VERSION 5.7 ;
  NOWIREEXTENSIONATPIN ON ;
  DIVIDERCHAR "/" ;
  BUSBITCHARS "[]" ;
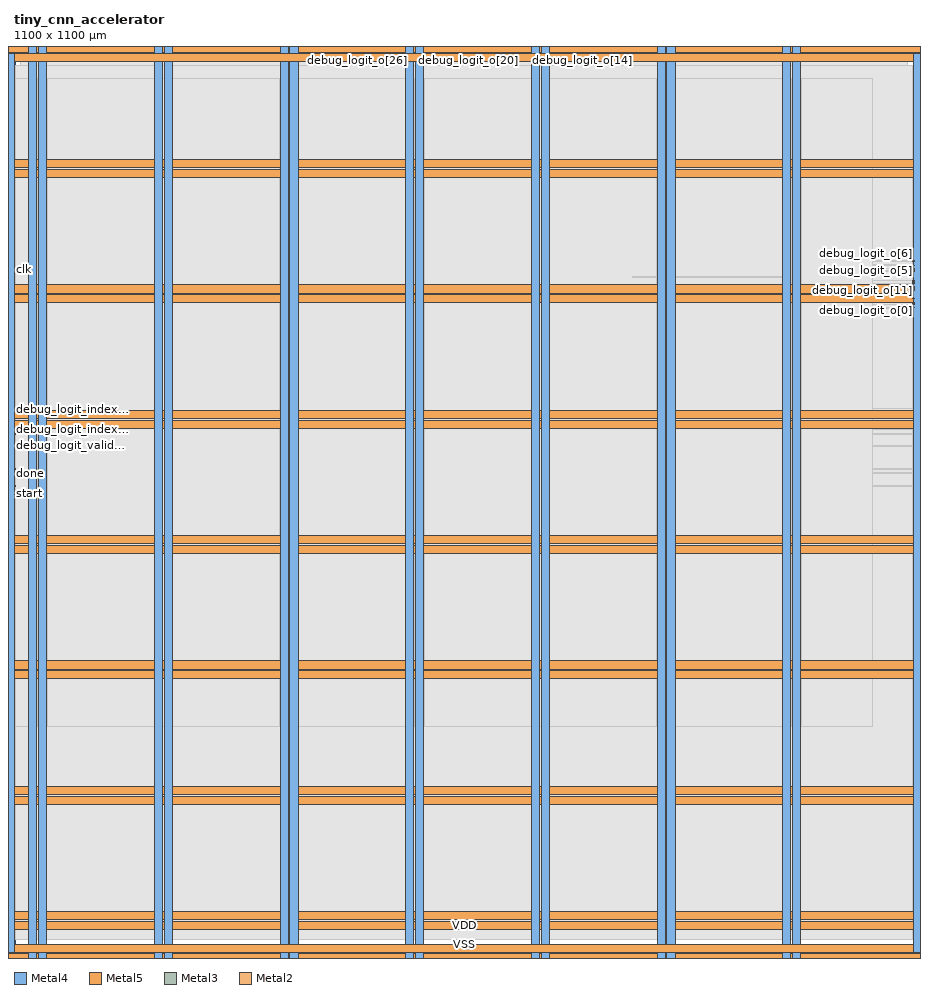
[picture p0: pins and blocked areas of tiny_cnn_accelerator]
MACRO tiny_cnn_accelerator
  CLASS BLOCK ;
  FOREIGN tiny_cnn_accelerator ;
  ORIGIN 0.000 0.000 ;
  SIZE 1100.000 BY 1100.000 ;
  PIN VDD
    DIRECTION INOUT ;
    USE POWER ;
    PORT
      LAYER Metal4 ;
        RECT -9.280 -0.320 0.720 1097.920 ;
    END
    PORT
      LAYER Metal4 ;
        RECT 1099.120 -0.320 1109.120 1097.920 ;
    END
    PORT
      LAYER Metal5 ;
        RECT -9.280 -0.320 1109.120 9.680 ;
    END
    PORT
      LAYER Metal5 ;
        RECT -9.280 1087.920 1109.120 1097.920 ;
    END
    PORT
      LAYER Metal4 ;
        RECT 18.040 -12.020 28.040 1109.620 ;
    END
    PORT
      LAYER Metal4 ;
        RECT 171.640 -12.020 181.640 1109.620 ;
    END
    PORT
      LAYER Metal4 ;
        RECT 325.240 -12.020 335.240 1109.620 ;
    END
    PORT
      LAYER Metal4 ;
        RECT 478.840 -12.020 488.840 1109.620 ;
    END
    PORT
      LAYER Metal4 ;
        RECT 632.440 -12.020 642.440 1109.620 ;
    END
    PORT
      LAYER Metal4 ;
        RECT 786.040 -12.020 796.040 1109.620 ;
    END
    PORT
      LAYER Metal4 ;
        RECT 939.640 -12.020 949.640 1109.620 ;
    END
    PORT
      LAYER Metal5 ;
        RECT -20.980 27.330 1120.820 37.330 ;
    END
    PORT
      LAYER Metal5 ;
        RECT -20.980 180.510 1120.820 190.510 ;
    END
    PORT
      LAYER Metal5 ;
        RECT -20.980 333.690 1120.820 343.690 ;
    END
    PORT
      LAYER Metal5 ;
        RECT -20.980 486.870 1120.820 496.870 ;
    END
    PORT
      LAYER Metal5 ;
        RECT -20.980 640.050 1120.820 650.050 ;
    END
    PORT
      LAYER Metal5 ;
        RECT -20.980 793.230 1120.820 803.230 ;
    END
    PORT
      LAYER Metal5 ;
        RECT -20.980 946.410 1120.820 956.410 ;
    END
  END VDD
  PIN VSS
    DIRECTION INOUT ;
    USE GROUND ;
    PORT
      LAYER Metal4 ;
        RECT -20.980 -12.020 -10.980 1109.620 ;
    END
    PORT
      LAYER Metal4 ;
        RECT 1110.820 -12.020 1120.820 1109.620 ;
    END
    PORT
      LAYER Metal5 ;
        RECT -20.980 -12.020 1120.820 -2.020 ;
    END
    PORT
      LAYER Metal5 ;
        RECT -20.980 1099.620 1120.820 1109.620 ;
    END
    PORT
      LAYER Metal4 ;
        RECT 30.040 -12.020 40.040 1109.620 ;
    END
    PORT
      LAYER Metal4 ;
        RECT 183.640 -12.020 193.640 1109.620 ;
    END
    PORT
      LAYER Metal4 ;
        RECT 337.240 -12.020 347.240 1109.620 ;
    END
    PORT
      LAYER Metal4 ;
        RECT 490.840 -12.020 500.840 1109.620 ;
    END
    PORT
      LAYER Metal4 ;
        RECT 644.440 -12.020 654.440 1109.620 ;
    END
    PORT
      LAYER Metal4 ;
        RECT 798.040 -12.020 808.040 1109.620 ;
    END
    PORT
      LAYER Metal4 ;
        RECT 951.640 -12.020 961.640 1109.620 ;
    END
    PORT
      LAYER Metal5 ;
        RECT -20.980 39.330 1120.820 49.330 ;
    END
    PORT
      LAYER Metal5 ;
        RECT -20.980 192.510 1120.820 202.510 ;
    END
    PORT
      LAYER Metal5 ;
        RECT -20.980 345.690 1120.820 355.690 ;
    END
    PORT
      LAYER Metal5 ;
        RECT -20.980 498.870 1120.820 508.870 ;
    END
    PORT
      LAYER Metal5 ;
        RECT -20.980 652.050 1120.820 662.050 ;
    END
    PORT
      LAYER Metal5 ;
        RECT -20.980 805.230 1120.820 815.230 ;
    END
    PORT
      LAYER Metal5 ;
        RECT -20.980 958.410 1120.820 968.410 ;
    END
  END VSS
  PIN busy
    DIRECTION OUTPUT ;
    USE SIGNAL ;
    ANTENNADIFFAREA 1.986000 ;
    PORT
      LAYER Metal3 ;
        RECT 0.000 590.170 2.000 590.870 ;
    END
  END busy
  PIN clk
    DIRECTION INPUT ;
    USE SIGNAL ;
    ANTENNAGATEAREA 4.738000 ;
    PORT
      LAYER Metal3 ;
        RECT 0.000 834.330 2.000 835.030 ;
    END
  END clk
  PIN debug_logit_index_o[0]
    DIRECTION OUTPUT ;
    USE SIGNAL ;
    ANTENNADIFFAREA 1.986000 ;
    PORT
      LAYER Metal3 ;
        RECT 0.000 638.330 2.000 639.030 ;
    END
  END debug_logit_index_o[0]
  PIN debug_logit_index_o[1]
    DIRECTION OUTPUT ;
    USE SIGNAL ;
    ANTENNADIFFAREA 1.986000 ;
    PORT
      LAYER Metal3 ;
        RECT 0.000 632.730 2.000 633.430 ;
    END
  END debug_logit_index_o[1]
  PIN debug_logit_index_o[2]
    DIRECTION OUTPUT ;
    USE SIGNAL ;
    ANTENNADIFFAREA 1.986000 ;
    PORT
      LAYER Metal3 ;
        RECT 0.000 662.970 2.000 663.670 ;
    END
  END debug_logit_index_o[2]
  PIN debug_logit_index_o[3]
    DIRECTION OUTPUT ;
    USE SIGNAL ;
    ANTENNADIFFAREA 1.986000 ;
    PORT
      LAYER Metal3 ;
        RECT 0.000 661.850 2.000 662.550 ;
    END
  END debug_logit_index_o[3]
  PIN debug_logit_o[0]
    DIRECTION OUTPUT ;
    USE SIGNAL ;
    ANTENNADIFFAREA 1.986000 ;
    PORT
      LAYER Metal3 ;
        RECT 1098.000 792.890 1100.000 793.590 ;
    END
  END debug_logit_o[0]
  PIN debug_logit_o[10]
    DIRECTION OUTPUT ;
    USE SIGNAL ;
    ANTENNADIFFAREA 1.986000 ;
    PORT
      LAYER Metal3 ;
        RECT 1098.000 811.930 1100.000 812.630 ;
    END
  END debug_logit_o[10]
  PIN debug_logit_o[11]
    DIRECTION OUTPUT ;
    USE SIGNAL ;
    ANTENNADIFFAREA 1.986000 ;
    PORT
      LAYER Metal3 ;
        RECT 1098.000 808.570 1100.000 809.270 ;
    END
  END debug_logit_o[11]
  PIN debug_logit_o[12]
    DIRECTION OUTPUT ;
    USE SIGNAL ;
    ANTENNADIFFAREA 1.986000 ;
    PORT
      LAYER Metal2 ;
        RECT 731.290 1098.000 731.990 1100.000 ;
    END
  END debug_logit_o[12]
  PIN debug_logit_o[13]
    DIRECTION OUTPUT ;
    USE SIGNAL ;
    ANTENNADIFFAREA 1.986000 ;
    PORT
      LAYER Metal2 ;
        RECT 713.370 1098.000 714.070 1100.000 ;
    END
  END debug_logit_o[13]
  PIN debug_logit_o[14]
    DIRECTION OUTPUT ;
    USE SIGNAL ;
    ANTENNADIFFAREA 1.986000 ;
    PORT
      LAYER Metal2 ;
        RECT 694.330 1098.000 695.030 1100.000 ;
    END
  END debug_logit_o[14]
  PIN debug_logit_o[15]
    DIRECTION OUTPUT ;
    USE SIGNAL ;
    ANTENNADIFFAREA 1.986000 ;
    PORT
      LAYER Metal2 ;
        RECT 657.370 1098.000 658.070 1100.000 ;
    END
  END debug_logit_o[15]
  PIN debug_logit_o[16]
    DIRECTION OUTPUT ;
    USE SIGNAL ;
    ANTENNADIFFAREA 1.986000 ;
    PORT
      LAYER Metal2 ;
        RECT 610.330 1098.000 611.030 1100.000 ;
    END
  END debug_logit_o[16]
  PIN debug_logit_o[17]
    DIRECTION OUTPUT ;
    USE SIGNAL ;
    ANTENNADIFFAREA 1.986000 ;
    PORT
      LAYER Metal2 ;
        RECT 606.970 1098.000 607.670 1100.000 ;
    END
  END debug_logit_o[17]
  PIN debug_logit_o[18]
    DIRECTION OUTPUT ;
    USE SIGNAL ;
    ANTENNADIFFAREA 1.986000 ;
    PORT
      LAYER Metal2 ;
        RECT 584.570 1098.000 585.270 1100.000 ;
    END
  END debug_logit_o[18]
  PIN debug_logit_o[19]
    DIRECTION OUTPUT ;
    USE SIGNAL ;
    ANTENNADIFFAREA 1.986000 ;
    PORT
      LAYER Metal2 ;
        RECT 566.650 1098.000 567.350 1100.000 ;
    END
  END debug_logit_o[19]
  PIN debug_logit_o[1]
    DIRECTION OUTPUT ;
    USE SIGNAL ;
    ANTENNADIFFAREA 1.986000 ;
    PORT
      LAYER Metal3 ;
        RECT 1098.000 817.530 1100.000 818.230 ;
    END
  END debug_logit_o[1]
  PIN debug_logit_o[20]
    DIRECTION OUTPUT ;
    USE SIGNAL ;
    ANTENNADIFFAREA 1.986000 ;
    PORT
      LAYER Metal2 ;
        RECT 555.450 1098.000 556.150 1100.000 ;
    END
  END debug_logit_o[20]
  PIN debug_logit_o[21]
    DIRECTION OUTPUT ;
    USE SIGNAL ;
    ANTENNADIFFAREA 1.986000 ;
    PORT
      LAYER Metal2 ;
        RECT 539.770 1098.000 540.470 1100.000 ;
    END
  END debug_logit_o[21]
  PIN debug_logit_o[22]
    DIRECTION OUTPUT ;
    USE SIGNAL ;
    ANTENNADIFFAREA 1.986000 ;
    PORT
      LAYER Metal2 ;
        RECT 477.050 1098.000 477.750 1100.000 ;
    END
  END debug_logit_o[22]
  PIN debug_logit_o[23]
    DIRECTION OUTPUT ;
    USE SIGNAL ;
    ANTENNADIFFAREA 1.986000 ;
    PORT
      LAYER Metal2 ;
        RECT 469.210 1098.000 469.910 1100.000 ;
    END
  END debug_logit_o[23]
  PIN debug_logit_o[24]
    DIRECTION OUTPUT ;
    USE SIGNAL ;
    ANTENNADIFFAREA 1.986000 ;
    PORT
      LAYER Metal2 ;
        RECT 435.610 1098.000 436.310 1100.000 ;
    END
  END debug_logit_o[24]
  PIN debug_logit_o[25]
    DIRECTION OUTPUT ;
    USE SIGNAL ;
    ANTENNADIFFAREA 1.986000 ;
    PORT
      LAYER Metal2 ;
        RECT 436.730 1098.000 437.430 1100.000 ;
    END
  END debug_logit_o[25]
  PIN debug_logit_o[26]
    DIRECTION OUTPUT ;
    USE SIGNAL ;
    ANTENNADIFFAREA 1.986000 ;
    PORT
      LAYER Metal2 ;
        RECT 419.930 1098.000 420.630 1100.000 ;
    END
  END debug_logit_o[26]
  PIN debug_logit_o[27]
    DIRECTION OUTPUT ;
    USE SIGNAL ;
    ANTENNADIFFAREA 1.986000 ;
    PORT
      LAYER Metal2 ;
        RECT 473.690 1098.000 474.390 1100.000 ;
    END
  END debug_logit_o[27]
  PIN debug_logit_o[28]
    DIRECTION OUTPUT ;
    USE SIGNAL ;
    ANTENNADIFFAREA 1.986000 ;
    PORT
      LAYER Metal2 ;
        RECT 500.570 1098.000 501.270 1100.000 ;
    END
  END debug_logit_o[28]
  PIN debug_logit_o[29]
    DIRECTION OUTPUT ;
    USE SIGNAL ;
    ANTENNADIFFAREA 1.986000 ;
    PORT
      LAYER Metal2 ;
        RECT 526.330 1098.000 527.030 1100.000 ;
    END
  END debug_logit_o[29]
  PIN debug_logit_o[2]
    DIRECTION OUTPUT ;
    USE SIGNAL ;
    ANTENNADIFFAREA 1.986000 ;
    PORT
      LAYER Metal3 ;
        RECT 1098.000 819.770 1100.000 820.470 ;
    END
  END debug_logit_o[2]
  PIN debug_logit_o[30]
    DIRECTION OUTPUT ;
    USE SIGNAL ;
    ANTENNADIFFAREA 1.986000 ;
    PORT
      LAYER Metal2 ;
        RECT 512.890 1098.000 513.590 1100.000 ;
    END
  END debug_logit_o[30]
  PIN debug_logit_o[31]
    DIRECTION OUTPUT ;
    USE SIGNAL ;
    ANTENNADIFFAREA 1.986000 ;
    PORT
      LAYER Metal2 ;
        RECT 535.290 1098.000 535.990 1100.000 ;
    END
  END debug_logit_o[31]
  PIN debug_logit_o[3]
    DIRECTION OUTPUT ;
    USE SIGNAL ;
    ANTENNADIFFAREA 1.986000 ;
    PORT
      LAYER Metal3 ;
        RECT 1098.000 791.770 1100.000 792.470 ;
    END
  END debug_logit_o[3]
  PIN debug_logit_o[4]
    DIRECTION OUTPUT ;
    USE SIGNAL ;
    ANTENNADIFFAREA 1.986000 ;
    PORT
      LAYER Metal3 ;
        RECT 1098.000 818.650 1100.000 819.350 ;
    END
  END debug_logit_o[4]
  PIN debug_logit_o[5]
    DIRECTION OUTPUT ;
    USE SIGNAL ;
    ANTENNADIFFAREA 1.986000 ;
    PORT
      LAYER Metal3 ;
        RECT 1098.000 832.090 1100.000 832.790 ;
    END
  END debug_logit_o[5]
  PIN debug_logit_o[6]
    DIRECTION OUTPUT ;
    USE SIGNAL ;
    ANTENNADIFFAREA 1.986000 ;
    PORT
      LAYER Metal3 ;
        RECT 1098.000 844.410 1100.000 845.110 ;
    END
  END debug_logit_o[6]
  PIN debug_logit_o[7]
    DIRECTION OUTPUT ;
    USE SIGNAL ;
    ANTENNADIFFAREA 1.986000 ;
    PORT
      LAYER Metal3 ;
        RECT 1098.000 834.330 1100.000 835.030 ;
    END
  END debug_logit_o[7]
  PIN debug_logit_o[8]
    DIRECTION OUTPUT ;
    USE SIGNAL ;
    ANTENNADIFFAREA 1.986000 ;
    PORT
      LAYER Metal3 ;
        RECT 1098.000 833.210 1100.000 833.910 ;
    END
  END debug_logit_o[8]
  PIN debug_logit_o[9]
    DIRECTION OUTPUT ;
    USE SIGNAL ;
    ANTENNADIFFAREA 1.986000 ;
    PORT
      LAYER Metal3 ;
        RECT 1098.000 838.810 1100.000 839.510 ;
    END
  END debug_logit_o[9]
  PIN debug_logit_valid_o
    DIRECTION OUTPUT ;
    USE SIGNAL ;
    ANTENNADIFFAREA 1.986000 ;
    PORT
      LAYER Metal3 ;
        RECT 0.000 618.170 2.000 618.870 ;
    END
  END debug_logit_valid_o
  PIN done
    DIRECTION OUTPUT ;
    USE SIGNAL ;
    ANTENNADIFFAREA 1.986000 ;
    PORT
      LAYER Metal3 ;
        RECT 0.000 584.570 2.000 585.270 ;
    END
  END done
  PIN predicted_class[0]
    DIRECTION OUTPUT ;
    USE SIGNAL ;
    ANTENNADIFFAREA 1.986000 ;
    PORT
      LAYER Metal3 ;
        RECT 1098.000 798.490 1100.000 799.190 ;
    END
  END predicted_class[0]
  PIN predicted_class[1]
    DIRECTION OUTPUT ;
    USE SIGNAL ;
    ANTENNADIFFAREA 1.986000 ;
    PORT
      LAYER Metal3 ;
        RECT 1098.000 809.690 1100.000 810.390 ;
    END
  END predicted_class[1]
  PIN predicted_class[2]
    DIRECTION OUTPUT ;
    USE SIGNAL ;
    ANTENNADIFFAREA 1.986000 ;
    PORT
      LAYER Metal3 ;
        RECT 1098.000 787.290 1100.000 787.990 ;
    END
  END predicted_class[2]
  PIN predicted_class[3]
    DIRECTION OUTPUT ;
    USE SIGNAL ;
    ANTENNADIFFAREA 1.986000 ;
    PORT
      LAYER Metal3 ;
        RECT 1098.000 813.050 1100.000 813.750 ;
    END
  END predicted_class[3]
  PIN rst_n
    DIRECTION INPUT ;
    USE SIGNAL ;
    ANTENNAGATEAREA 0.498500 ;
    PORT
      LAYER Metal3 ;
        RECT 0.000 833.210 2.000 833.910 ;
    END
  END rst_n
  PIN start
    DIRECTION INPUT ;
    USE SIGNAL ;
    ANTENNAGATEAREA 0.498500 ;
    PORT
      LAYER Metal3 ;
        RECT 0.000 568.890 2.000 569.590 ;
    END
  END start
  OBS
      LAYER Nwell ;
        RECT 6.290 15.250 1093.550 1082.350 ;
      LAYER Metal1 ;
        RECT 6.720 15.380 1093.120 1082.220 ;
      LAYER Metal2 ;
        RECT 8.540 1097.700 419.630 1098.580 ;
        RECT 420.930 1097.700 435.310 1098.580 ;
        RECT 437.730 1097.700 468.910 1098.580 ;
        RECT 470.210 1097.700 473.390 1098.580 ;
        RECT 474.690 1097.700 476.750 1098.580 ;
        RECT 478.050 1097.700 500.270 1098.580 ;
        RECT 501.570 1097.700 512.590 1098.580 ;
        RECT 513.890 1097.700 526.030 1098.580 ;
        RECT 527.330 1097.700 534.990 1098.580 ;
        RECT 536.290 1097.700 539.470 1098.580 ;
        RECT 540.770 1097.700 555.150 1098.580 ;
        RECT 556.450 1097.700 566.350 1098.580 ;
        RECT 567.650 1097.700 584.270 1098.580 ;
        RECT 585.570 1097.700 606.670 1098.580 ;
        RECT 607.970 1097.700 610.030 1098.580 ;
        RECT 611.330 1097.700 657.070 1098.580 ;
        RECT 658.370 1097.700 694.030 1098.580 ;
        RECT 695.330 1097.700 713.070 1098.580 ;
        RECT 714.370 1097.700 730.990 1098.580 ;
        RECT 732.290 1097.700 1091.860 1098.580 ;
        RECT 8.540 15.490 1091.860 1097.700 ;
      LAYER Metal3 ;
        RECT 1.770 845.410 1098.000 1084.020 ;
        RECT 1.770 844.110 1097.700 845.410 ;
        RECT 1.770 839.810 1098.000 844.110 ;
        RECT 1.770 838.510 1097.700 839.810 ;
        RECT 1.770 835.330 1098.000 838.510 ;
        RECT 2.300 832.910 1097.700 835.330 ;
        RECT 1.770 831.790 1097.700 832.910 ;
        RECT 1.770 820.770 1098.000 831.790 ;
        RECT 1.770 817.230 1097.700 820.770 ;
        RECT 1.770 814.050 1098.000 817.230 ;
        RECT 1.770 811.630 1097.700 814.050 ;
        RECT 1.770 810.690 1098.000 811.630 ;
        RECT 1.770 808.270 1097.700 810.690 ;
        RECT 1.770 799.490 1098.000 808.270 ;
        RECT 1.770 798.190 1097.700 799.490 ;
        RECT 1.770 793.890 1098.000 798.190 ;
        RECT 1.770 791.470 1097.700 793.890 ;
        RECT 1.770 788.290 1098.000 791.470 ;
        RECT 1.770 786.990 1097.700 788.290 ;
        RECT 1.770 663.970 1098.000 786.990 ;
        RECT 2.300 661.550 1098.000 663.970 ;
        RECT 1.770 639.330 1098.000 661.550 ;
        RECT 2.300 638.030 1098.000 639.330 ;
        RECT 1.770 633.730 1098.000 638.030 ;
        RECT 2.300 632.430 1098.000 633.730 ;
        RECT 1.770 619.170 1098.000 632.430 ;
        RECT 2.300 617.870 1098.000 619.170 ;
        RECT 1.770 591.170 1098.000 617.870 ;
        RECT 2.300 589.870 1098.000 591.170 ;
        RECT 1.770 585.570 1098.000 589.870 ;
        RECT 2.300 584.270 1098.000 585.570 ;
        RECT 1.770 569.890 1098.000 584.270 ;
        RECT 2.300 568.590 1098.000 569.890 ;
        RECT 1.770 15.540 1098.000 568.590 ;
      LAYER Metal4 ;
        RECT 1.820 275.050 17.740 1067.270 ;
        RECT 28.340 275.050 29.740 1067.270 ;
        RECT 40.340 275.050 171.340 1067.270 ;
        RECT 181.940 275.050 183.340 1067.270 ;
        RECT 193.940 275.050 324.940 1067.270 ;
        RECT 335.540 275.050 336.940 1067.270 ;
        RECT 347.540 275.050 478.540 1067.270 ;
        RECT 489.140 275.050 490.540 1067.270 ;
        RECT 501.140 275.050 632.140 1067.270 ;
        RECT 642.740 275.050 644.140 1067.270 ;
        RECT 654.740 275.050 785.740 1067.270 ;
        RECT 796.340 275.050 797.740 1067.270 ;
        RECT 808.340 275.050 939.340 1067.270 ;
        RECT 949.940 275.050 951.340 1067.270 ;
        RECT 961.940 275.050 1048.740 1067.270 ;
      LAYER Metal5 ;
        RECT 755.500 824.630 962.580 825.070 ;
  END
END tiny_cnn_accelerator
END LIBRARY

